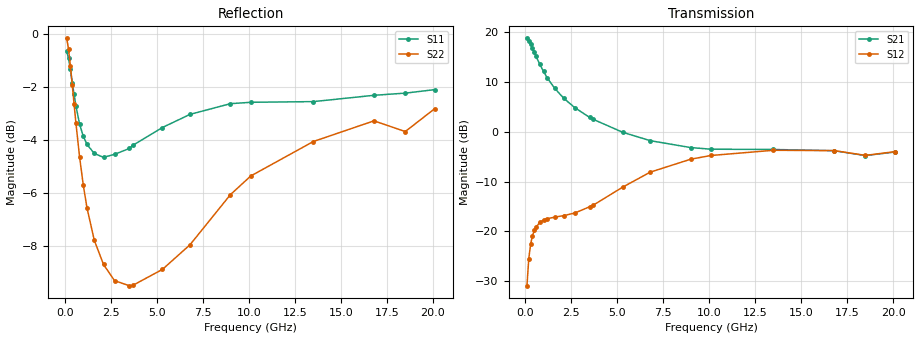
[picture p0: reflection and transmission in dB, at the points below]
!  Infineon Technologies AG
! BFR380L3 , PF131585-7, No.6, Th 09.10.01, soldered on pcb-board, measured with PP GSG850
!  Vce=4.0 V,  Ic=2.5 mA
! Common Emitter S-Parameters:  15. November 2001
#  GHz  S  MA  R  50
! f  S11  S21  S12  S22
! GHz  Mag  Ang  Mag  Ang  Mag  Ang  Mag  Ang
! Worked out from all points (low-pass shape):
!   201 points, 100 MHz to 20.1 GHz, reference 50 ohm
!   highest |S21| = 18.79 dB at 100 MHz (marker M1); lowest = -4.8 dB at 18.5 GHz (marker M2)
!   |S21| within 3 dB of the highest: start of sweep to 523.2 MHz
!   lowest |S11| = -4.7 dB at 2.1 GHz (marker M3), VSWR 3.81, Z = 13.2 - j3.02 ohm
!   |S11| at or under -10 dB: nowhere
!   |S22| runs from -9.5 to -0.2 dB; largest |S21 - S12| = 8.7
!   S11 on the Smith chart (normalised r, x): 100 MHz: 1.41, -5.83; 500 MHz: 0.31, -1.14; 1.2 GHz: 0.27, -0.37; 3.7 GHz: 0.25, +0.24; 9 GHz: 0.32, +1.04; 20.1 GHz: 1.00, +2.53
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0.1  0.9263 -18.4  8.699 167.1  0.02852 78.5  0.9801 -9.9
0.2  0.8981 -36.3  8.159 155.3  0.05347 69.8  0.9346 -19.1
0.3  0.8567 -53.0  7.573 144.4  0.07457 61.4  0.8698 -26.9
0.4  0.8083 -67.3  6.933 135.1  0.09019 54.6  0.8011 -33.4
0.5  0.7682 -80.1  6.297 127.1  0.1023 49.2  0.7365 -38.6
0.6  0.7309 -91.3  5.719 120.2  0.1112 44.9  0.6781 -42.8
0.8  0.6752 -110.1  4.766 109.0  0.123 38.7  0.5847 -48.9
1  0.6401 -124.8  4.049 100.2  0.1298 34.9  0.5178 -53.0
1.2  0.6181 -136.7  3.499 93.0  0.1341 32.8  0.4692 -56.3
1.6  0.5941 -155.4  2.753 81.2  0.1392 31.5  0.4071 -61.7
2.1  0.5842 -172.6  2.176 69.4  0.1442 33.1  0.3666 -68.1
2.7  0.5919 171.6  1.751 57.6  0.1531 37.9  0.3417 -77.0
3.5  0.6071 154.3  1.401 44.3  0.1768 44.8  0.3343 -90.1
3.7  0.6157 151.1  1.338 41.7  0.1835 46.0  0.3349 -94.4
5.3  0.6651 125.4  0.9915 22.3  0.2784 49.8  0.3588 -126.7
6.8  0.7042 106.0  0.8162 10.5  0.3941 42.7  0.3994 -158.9
8.999999  0.7378 84.8  0.6958 0.5  0.5317 25.9  0.4968 161.9
10.1  0.7422 76.4  0.6702 -3.5  0.5795 17.0  0.5386 144.8
13.5  0.7444 58.4  0.6657 -17.4  0.6536 -7.6  0.6257 106.0
16.8  0.7651 47.1  0.6473 -29.6  0.6483 -24.9  0.6847 80.5
18.5  0.7724 45.6  0.5781 -37.7  0.5807 -33.5  0.6535 74.0
20.1  0.7842 38.3  0.6281 -41.6  0.6335 -38.8  0.7219 62.7
